VERSION 5.7 ;
BUSBITCHARS "[]" ;
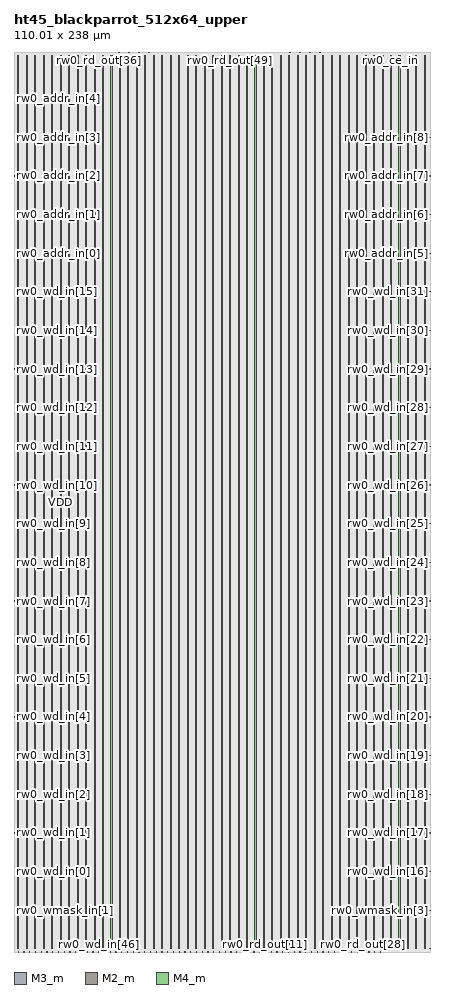
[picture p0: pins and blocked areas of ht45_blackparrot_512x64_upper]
MACRO ht45_blackparrot_512x64_upper
  FOREIGN ht45_blackparrot_512x64_upper 0 0 ;
  SYMMETRY X Y R90 ;
  SIZE 110.010 BY 238.000 ;
  CLASS COVER ;
  PIN rw0_wmask_in[0]
    DIRECTION INPUT ;
    USE SIGNAL ;
    SHAPE ABUTMENT ;
    PORT
      LAYER M3_m ;
      RECT 0.000 0.805 0.210 0.875 ;
    END
  END rw0_wmask_in[0]
  PIN rw0_wmask_in[1]
    DIRECTION INPUT ;
    USE SIGNAL ;
    SHAPE ABUTMENT ;
    PORT
      LAYER M3_m ;
      RECT 0.000 11.025 0.210 11.095 ;
    END
  END rw0_wmask_in[1]
  PIN rw0_wmask_in[2]
    DIRECTION INPUT ;
    USE SIGNAL ;
    SHAPE ABUTMENT ;
    PORT
      LAYER M3_m ;
      RECT 109.800 0.805 110.010 0.875 ;
    END
  END rw0_wmask_in[2]
  PIN rw0_wmask_in[3]
    DIRECTION INPUT ;
    USE SIGNAL ;
    SHAPE ABUTMENT ;
    PORT
      LAYER M3_m ;
      RECT 109.800 11.025 110.010 11.095 ;
    END
  END rw0_wmask_in[3]
  PIN rw0_wmask_in[4]
    DIRECTION INPUT ;
    USE SIGNAL ;
    SHAPE ABUTMENT ;
    PORT
      LAYER M2_m ;
      RECT 1.105 237.790 1.175 238.000 ;
    END
  END rw0_wmask_in[4]
  PIN rw0_wmask_in[5]
    DIRECTION INPUT ;
    USE SIGNAL ;
    SHAPE ABUTMENT ;
    PORT
      LAYER M2_m ;
      RECT 3.765 237.790 3.835 238.000 ;
    END
  END rw0_wmask_in[5]
  PIN rw0_wmask_in[6]
    DIRECTION INPUT ;
    USE SIGNAL ;
    SHAPE ABUTMENT ;
    PORT
      LAYER M2_m ;
      RECT 6.425 237.790 6.495 238.000 ;
    END
  END rw0_wmask_in[6]
  PIN rw0_wmask_in[7]
    DIRECTION INPUT ;
    USE SIGNAL ;
    SHAPE ABUTMENT ;
    PORT
      LAYER M2_m ;
      RECT 9.085 237.790 9.155 238.000 ;
    END
  END rw0_wmask_in[7]
  PIN rw0_wd_in[0]
    DIRECTION INPUT ;
    USE SIGNAL ;
    SHAPE ABUTMENT ;
    PORT
      LAYER M3_m ;
      RECT 0.000 21.245 0.210 21.315 ;
    END
  END rw0_wd_in[0]
  PIN rw0_wd_in[1]
    DIRECTION INPUT ;
    USE SIGNAL ;
    SHAPE ABUTMENT ;
    PORT
      LAYER M3_m ;
      RECT 0.000 31.465 0.210 31.535 ;
    END
  END rw0_wd_in[1]
  PIN rw0_wd_in[2]
    DIRECTION INPUT ;
    USE SIGNAL ;
    SHAPE ABUTMENT ;
    PORT
      LAYER M3_m ;
      RECT 0.000 41.685 0.210 41.755 ;
    END
  END rw0_wd_in[2]
  PIN rw0_wd_in[3]
    DIRECTION INPUT ;
    USE SIGNAL ;
    SHAPE ABUTMENT ;
    PORT
      LAYER M3_m ;
      RECT 0.000 51.905 0.210 51.975 ;
    END
  END rw0_wd_in[3]
  PIN rw0_wd_in[4]
    DIRECTION INPUT ;
    USE SIGNAL ;
    SHAPE ABUTMENT ;
    PORT
      LAYER M3_m ;
      RECT 0.000 62.125 0.210 62.195 ;
    END
  END rw0_wd_in[4]
  PIN rw0_wd_in[5]
    DIRECTION INPUT ;
    USE SIGNAL ;
    SHAPE ABUTMENT ;
    PORT
      LAYER M3_m ;
      RECT 0.000 72.345 0.210 72.415 ;
    END
  END rw0_wd_in[5]
  PIN rw0_wd_in[6]
    DIRECTION INPUT ;
    USE SIGNAL ;
    SHAPE ABUTMENT ;
    PORT
      LAYER M3_m ;
      RECT 0.000 82.565 0.210 82.635 ;
    END
  END rw0_wd_in[6]
  PIN rw0_wd_in[7]
    DIRECTION INPUT ;
    USE SIGNAL ;
    SHAPE ABUTMENT ;
    PORT
      LAYER M3_m ;
      RECT 0.000 92.785 0.210 92.855 ;
    END
  END rw0_wd_in[7]
  PIN rw0_wd_in[8]
    DIRECTION INPUT ;
    USE SIGNAL ;
    SHAPE ABUTMENT ;
    PORT
      LAYER M3_m ;
      RECT 0.000 103.005 0.210 103.075 ;
    END
  END rw0_wd_in[8]
  PIN rw0_wd_in[9]
    DIRECTION INPUT ;
    USE SIGNAL ;
    SHAPE ABUTMENT ;
    PORT
      LAYER M3_m ;
      RECT 0.000 113.225 0.210 113.295 ;
    END
  END rw0_wd_in[9]
  PIN rw0_wd_in[10]
    DIRECTION INPUT ;
    USE SIGNAL ;
    SHAPE ABUTMENT ;
    PORT
      LAYER M3_m ;
      RECT 0.000 123.445 0.210 123.515 ;
    END
  END rw0_wd_in[10]
  PIN rw0_wd_in[11]
    DIRECTION INPUT ;
    USE SIGNAL ;
    SHAPE ABUTMENT ;
    PORT
      LAYER M3_m ;
      RECT 0.000 133.665 0.210 133.735 ;
    END
  END rw0_wd_in[11]
  PIN rw0_wd_in[12]
    DIRECTION INPUT ;
    USE SIGNAL ;
    SHAPE ABUTMENT ;
    PORT
      LAYER M3_m ;
      RECT 0.000 143.885 0.210 143.955 ;
    END
  END rw0_wd_in[12]
  PIN rw0_wd_in[13]
    DIRECTION INPUT ;
    USE SIGNAL ;
    SHAPE ABUTMENT ;
    PORT
      LAYER M3_m ;
      RECT 0.000 154.105 0.210 154.175 ;
    END
  END rw0_wd_in[13]
  PIN rw0_wd_in[14]
    DIRECTION INPUT ;
    USE SIGNAL ;
    SHAPE ABUTMENT ;
    PORT
      LAYER M3_m ;
      RECT 0.000 164.325 0.210 164.395 ;
    END
  END rw0_wd_in[14]
  PIN rw0_wd_in[15]
    DIRECTION INPUT ;
    USE SIGNAL ;
    SHAPE ABUTMENT ;
    PORT
      LAYER M3_m ;
      RECT 0.000 174.545 0.210 174.615 ;
    END
  END rw0_wd_in[15]
  PIN rw0_wd_in[16]
    DIRECTION INPUT ;
    USE SIGNAL ;
    SHAPE ABUTMENT ;
    PORT
      LAYER M3_m ;
      RECT 109.800 21.245 110.010 21.315 ;
    END
  END rw0_wd_in[16]
  PIN rw0_wd_in[17]
    DIRECTION INPUT ;
    USE SIGNAL ;
    SHAPE ABUTMENT ;
    PORT
      LAYER M3_m ;
      RECT 109.800 31.465 110.010 31.535 ;
    END
  END rw0_wd_in[17]
  PIN rw0_wd_in[18]
    DIRECTION INPUT ;
    USE SIGNAL ;
    SHAPE ABUTMENT ;
    PORT
      LAYER M3_m ;
      RECT 109.800 41.685 110.010 41.755 ;
    END
  END rw0_wd_in[18]
  PIN rw0_wd_in[19]
    DIRECTION INPUT ;
    USE SIGNAL ;
    SHAPE ABUTMENT ;
    PORT
      LAYER M3_m ;
      RECT 109.800 51.905 110.010 51.975 ;
    END
  END rw0_wd_in[19]
  PIN rw0_wd_in[20]
    DIRECTION INPUT ;
    USE SIGNAL ;
    SHAPE ABUTMENT ;
    PORT
      LAYER M3_m ;
      RECT 109.800 62.125 110.010 62.195 ;
    END
  END rw0_wd_in[20]
  PIN rw0_wd_in[21]
    DIRECTION INPUT ;
    USE SIGNAL ;
    SHAPE ABUTMENT ;
    PORT
      LAYER M3_m ;
      RECT 109.800 72.345 110.010 72.415 ;
    END
  END rw0_wd_in[21]
  PIN rw0_wd_in[22]
    DIRECTION INPUT ;
    USE SIGNAL ;
    SHAPE ABUTMENT ;
    PORT
      LAYER M3_m ;
      RECT 109.800 82.565 110.010 82.635 ;
    END
  END rw0_wd_in[22]
  PIN rw0_wd_in[23]
    DIRECTION INPUT ;
    USE SIGNAL ;
    SHAPE ABUTMENT ;
    PORT
      LAYER M3_m ;
      RECT 109.800 92.785 110.010 92.855 ;
    END
  END rw0_wd_in[23]
  PIN rw0_wd_in[24]
    DIRECTION INPUT ;
    USE SIGNAL ;
    SHAPE ABUTMENT ;
    PORT
      LAYER M3_m ;
      RECT 109.800 103.005 110.010 103.075 ;
    END
  END rw0_wd_in[24]
  PIN rw0_wd_in[25]
    DIRECTION INPUT ;
    USE SIGNAL ;
    SHAPE ABUTMENT ;
    PORT
      LAYER M3_m ;
      RECT 109.800 113.225 110.010 113.295 ;
    END
  END rw0_wd_in[25]
  PIN rw0_wd_in[26]
    DIRECTION INPUT ;
    USE SIGNAL ;
    SHAPE ABUTMENT ;
    PORT
      LAYER M3_m ;
      RECT 109.800 123.445 110.010 123.515 ;
    END
  END rw0_wd_in[26]
  PIN rw0_wd_in[27]
    DIRECTION INPUT ;
    USE SIGNAL ;
    SHAPE ABUTMENT ;
    PORT
      LAYER M3_m ;
      RECT 109.800 133.665 110.010 133.735 ;
    END
  END rw0_wd_in[27]
  PIN rw0_wd_in[28]
    DIRECTION INPUT ;
    USE SIGNAL ;
    SHAPE ABUTMENT ;
    PORT
      LAYER M3_m ;
      RECT 109.800 143.885 110.010 143.955 ;
    END
  END rw0_wd_in[28]
  PIN rw0_wd_in[29]
    DIRECTION INPUT ;
    USE SIGNAL ;
    SHAPE ABUTMENT ;
    PORT
      LAYER M3_m ;
      RECT 109.800 154.105 110.010 154.175 ;
    END
  END rw0_wd_in[29]
  PIN rw0_wd_in[30]
    DIRECTION INPUT ;
    USE SIGNAL ;
    SHAPE ABUTMENT ;
    PORT
      LAYER M3_m ;
      RECT 109.800 164.325 110.010 164.395 ;
    END
  END rw0_wd_in[30]
  PIN rw0_wd_in[31]
    DIRECTION INPUT ;
    USE SIGNAL ;
    SHAPE ABUTMENT ;
    PORT
      LAYER M3_m ;
      RECT 109.800 174.545 110.010 174.615 ;
    END
  END rw0_wd_in[31]
  PIN rw0_wd_in[32]
    DIRECTION INPUT ;
    USE SIGNAL ;
    SHAPE ABUTMENT ;
    PORT
      LAYER M2_m ;
      RECT 1.105 0.000 1.175 0.210 ;
    END
  END rw0_wd_in[32]
  PIN rw0_wd_in[33]
    DIRECTION INPUT ;
    USE SIGNAL ;
    SHAPE ABUTMENT ;
    PORT
      LAYER M2_m ;
      RECT 2.625 0.000 2.695 0.210 ;
    END
  END rw0_wd_in[33]
  PIN rw0_wd_in[34]
    DIRECTION INPUT ;
    USE SIGNAL ;
    SHAPE ABUTMENT ;
    PORT
      LAYER M2_m ;
      RECT 4.145 0.000 4.215 0.210 ;
    END
  END rw0_wd_in[34]
  PIN rw0_wd_in[35]
    DIRECTION INPUT ;
    USE SIGNAL ;
    SHAPE ABUTMENT ;
    PORT
      LAYER M2_m ;
      RECT 5.665 0.000 5.735 0.210 ;
    END
  END rw0_wd_in[35]
  PIN rw0_wd_in[36]
    DIRECTION INPUT ;
    USE SIGNAL ;
    SHAPE ABUTMENT ;
    PORT
      LAYER M2_m ;
      RECT 7.185 0.000 7.255 0.210 ;
    END
  END rw0_wd_in[36]
  PIN rw0_wd_in[37]
    DIRECTION INPUT ;
    USE SIGNAL ;
    SHAPE ABUTMENT ;
    PORT
      LAYER M2_m ;
      RECT 8.705 0.000 8.775 0.210 ;
    END
  END rw0_wd_in[37]
  PIN rw0_wd_in[38]
    DIRECTION INPUT ;
    USE SIGNAL ;
    SHAPE ABUTMENT ;
    PORT
      LAYER M2_m ;
      RECT 10.225 0.000 10.295 0.210 ;
    END
  END rw0_wd_in[38]
  PIN rw0_wd_in[39]
    DIRECTION INPUT ;
    USE SIGNAL ;
    SHAPE ABUTMENT ;
    PORT
      LAYER M2_m ;
      RECT 11.745 0.000 11.815 0.210 ;
    END
  END rw0_wd_in[39]
  PIN rw0_wd_in[40]
    DIRECTION INPUT ;
    USE SIGNAL ;
    SHAPE ABUTMENT ;
    PORT
      LAYER M2_m ;
      RECT 13.265 0.000 13.335 0.210 ;
    END
  END rw0_wd_in[40]
  PIN rw0_wd_in[41]
    DIRECTION INPUT ;
    USE SIGNAL ;
    SHAPE ABUTMENT ;
    PORT
      LAYER M2_m ;
      RECT 14.785 0.000 14.855 0.210 ;
    END
  END rw0_wd_in[41]
  PIN rw0_wd_in[42]
    DIRECTION INPUT ;
    USE SIGNAL ;
    SHAPE ABUTMENT ;
    PORT
      LAYER M2_m ;
      RECT 16.305 0.000 16.375 0.210 ;
    END
  END rw0_wd_in[42]
  PIN rw0_wd_in[43]
    DIRECTION INPUT ;
    USE SIGNAL ;
    SHAPE ABUTMENT ;
    PORT
      LAYER M2_m ;
      RECT 17.825 0.000 17.895 0.210 ;
    END
  END rw0_wd_in[43]
  PIN rw0_wd_in[44]
    DIRECTION INPUT ;
    USE SIGNAL ;
    SHAPE ABUTMENT ;
    PORT
      LAYER M2_m ;
      RECT 19.345 0.000 19.415 0.210 ;
    END
  END rw0_wd_in[44]
  PIN rw0_wd_in[45]
    DIRECTION INPUT ;
    USE SIGNAL ;
    SHAPE ABUTMENT ;
    PORT
      LAYER M2_m ;
      RECT 20.865 0.000 20.935 0.210 ;
    END
  END rw0_wd_in[45]
  PIN rw0_wd_in[46]
    DIRECTION INPUT ;
    USE SIGNAL ;
    SHAPE ABUTMENT ;
    PORT
      LAYER M2_m ;
      RECT 22.385 0.000 22.455 0.210 ;
    END
  END rw0_wd_in[46]
  PIN rw0_wd_in[47]
    DIRECTION INPUT ;
    USE SIGNAL ;
    SHAPE ABUTMENT ;
    PORT
      LAYER M2_m ;
      RECT 23.905 0.000 23.975 0.210 ;
    END
  END rw0_wd_in[47]
  PIN rw0_wd_in[48]
    DIRECTION INPUT ;
    USE SIGNAL ;
    SHAPE ABUTMENT ;
    PORT
      LAYER M2_m ;
      RECT 25.425 0.000 25.495 0.210 ;
    END
  END rw0_wd_in[48]
  PIN rw0_wd_in[49]
    DIRECTION INPUT ;
    USE SIGNAL ;
    SHAPE ABUTMENT ;
    PORT
      LAYER M2_m ;
      RECT 26.945 0.000 27.015 0.210 ;
    END
  END rw0_wd_in[49]
  PIN rw0_wd_in[50]
    DIRECTION INPUT ;
    USE SIGNAL ;
    SHAPE ABUTMENT ;
    PORT
      LAYER M2_m ;
      RECT 28.465 0.000 28.535 0.210 ;
    END
  END rw0_wd_in[50]
  PIN rw0_wd_in[51]
    DIRECTION INPUT ;
    USE SIGNAL ;
    SHAPE ABUTMENT ;
    PORT
      LAYER M2_m ;
      RECT 29.985 0.000 30.055 0.210 ;
    END
  END rw0_wd_in[51]
  PIN rw0_wd_in[52]
    DIRECTION INPUT ;
    USE SIGNAL ;
    SHAPE ABUTMENT ;
    PORT
      LAYER M2_m ;
      RECT 31.505 0.000 31.575 0.210 ;
    END
  END rw0_wd_in[52]
  PIN rw0_wd_in[53]
    DIRECTION INPUT ;
    USE SIGNAL ;
    SHAPE ABUTMENT ;
    PORT
      LAYER M2_m ;
      RECT 33.025 0.000 33.095 0.210 ;
    END
  END rw0_wd_in[53]
  PIN rw0_wd_in[54]
    DIRECTION INPUT ;
    USE SIGNAL ;
    SHAPE ABUTMENT ;
    PORT
      LAYER M2_m ;
      RECT 34.545 0.000 34.615 0.210 ;
    END
  END rw0_wd_in[54]
  PIN rw0_wd_in[55]
    DIRECTION INPUT ;
    USE SIGNAL ;
    SHAPE ABUTMENT ;
    PORT
      LAYER M2_m ;
      RECT 36.065 0.000 36.135 0.210 ;
    END
  END rw0_wd_in[55]
  PIN rw0_wd_in[56]
    DIRECTION INPUT ;
    USE SIGNAL ;
    SHAPE ABUTMENT ;
    PORT
      LAYER M2_m ;
      RECT 37.585 0.000 37.655 0.210 ;
    END
  END rw0_wd_in[56]
  PIN rw0_wd_in[57]
    DIRECTION INPUT ;
    USE SIGNAL ;
    SHAPE ABUTMENT ;
    PORT
      LAYER M2_m ;
      RECT 39.105 0.000 39.175 0.210 ;
    END
  END rw0_wd_in[57]
  PIN rw0_wd_in[58]
    DIRECTION INPUT ;
    USE SIGNAL ;
    SHAPE ABUTMENT ;
    PORT
      LAYER M2_m ;
      RECT 40.625 0.000 40.695 0.210 ;
    END
  END rw0_wd_in[58]
  PIN rw0_wd_in[59]
    DIRECTION INPUT ;
    USE SIGNAL ;
    SHAPE ABUTMENT ;
    PORT
      LAYER M2_m ;
      RECT 42.145 0.000 42.215 0.210 ;
    END
  END rw0_wd_in[59]
  PIN rw0_wd_in[60]
    DIRECTION INPUT ;
    USE SIGNAL ;
    SHAPE ABUTMENT ;
    PORT
      LAYER M2_m ;
      RECT 43.665 0.000 43.735 0.210 ;
    END
  END rw0_wd_in[60]
  PIN rw0_wd_in[61]
    DIRECTION INPUT ;
    USE SIGNAL ;
    SHAPE ABUTMENT ;
    PORT
      LAYER M2_m ;
      RECT 45.185 0.000 45.255 0.210 ;
    END
  END rw0_wd_in[61]
  PIN rw0_wd_in[62]
    DIRECTION INPUT ;
    USE SIGNAL ;
    SHAPE ABUTMENT ;
    PORT
      LAYER M2_m ;
      RECT 46.705 0.000 46.775 0.210 ;
    END
  END rw0_wd_in[62]
  PIN rw0_wd_in[63]
    DIRECTION INPUT ;
    USE SIGNAL ;
    SHAPE ABUTMENT ;
    PORT
      LAYER M2_m ;
      RECT 48.225 0.000 48.295 0.210 ;
    END
  END rw0_wd_in[63]
  PIN rw0_rd_out[0]
    DIRECTION OUTPUT ;
    USE SIGNAL ;
    SHAPE ABUTMENT ;
    PORT
      LAYER M2_m ;
      RECT 49.745 0.000 49.815 0.210 ;
    END
  END rw0_rd_out[0]
  PIN rw0_rd_out[1]
    DIRECTION OUTPUT ;
    USE SIGNAL ;
    SHAPE ABUTMENT ;
    PORT
      LAYER M2_m ;
      RECT 51.265 0.000 51.335 0.210 ;
    END
  END rw0_rd_out[1]
  PIN rw0_rd_out[2]
    DIRECTION OUTPUT ;
    USE SIGNAL ;
    SHAPE ABUTMENT ;
    PORT
      LAYER M2_m ;
      RECT 52.785 0.000 52.855 0.210 ;
    END
  END rw0_rd_out[2]
  PIN rw0_rd_out[3]
    DIRECTION OUTPUT ;
    USE SIGNAL ;
    SHAPE ABUTMENT ;
    PORT
      LAYER M2_m ;
      RECT 54.305 0.000 54.375 0.210 ;
    END
  END rw0_rd_out[3]
  PIN rw0_rd_out[4]
    DIRECTION OUTPUT ;
    USE SIGNAL ;
    SHAPE ABUTMENT ;
    PORT
      LAYER M2_m ;
      RECT 55.825 0.000 55.895 0.210 ;
    END
  END rw0_rd_out[4]
  PIN rw0_rd_out[5]
    DIRECTION OUTPUT ;
    USE SIGNAL ;
    SHAPE ABUTMENT ;
    PORT
      LAYER M2_m ;
      RECT 57.345 0.000 57.415 0.210 ;
    END
  END rw0_rd_out[5]
  PIN rw0_rd_out[6]
    DIRECTION OUTPUT ;
    USE SIGNAL ;
    SHAPE ABUTMENT ;
    PORT
      LAYER M2_m ;
      RECT 58.865 0.000 58.935 0.210 ;
    END
  END rw0_rd_out[6]
  PIN rw0_rd_out[7]
    DIRECTION OUTPUT ;
    USE SIGNAL ;
    SHAPE ABUTMENT ;
    PORT
      LAYER M2_m ;
      RECT 60.385 0.000 60.455 0.210 ;
    END
  END rw0_rd_out[7]
  PIN rw0_rd_out[8]
    DIRECTION OUTPUT ;
    USE SIGNAL ;
    SHAPE ABUTMENT ;
    PORT
      LAYER M2_m ;
      RECT 61.905 0.000 61.975 0.210 ;
    END
  END rw0_rd_out[8]
  PIN rw0_rd_out[9]
    DIRECTION OUTPUT ;
    USE SIGNAL ;
    SHAPE ABUTMENT ;
    PORT
      LAYER M2_m ;
      RECT 63.425 0.000 63.495 0.210 ;
    END
  END rw0_rd_out[9]
  PIN rw0_rd_out[10]
    DIRECTION OUTPUT ;
    USE SIGNAL ;
    SHAPE ABUTMENT ;
    PORT
      LAYER M2_m ;
      RECT 64.945 0.000 65.015 0.210 ;
    END
  END rw0_rd_out[10]
  PIN rw0_rd_out[11]
    DIRECTION OUTPUT ;
    USE SIGNAL ;
    SHAPE ABUTMENT ;
    PORT
      LAYER M2_m ;
      RECT 66.465 0.000 66.535 0.210 ;
    END
  END rw0_rd_out[11]
  PIN rw0_rd_out[12]
    DIRECTION OUTPUT ;
    USE SIGNAL ;
    SHAPE ABUTMENT ;
    PORT
      LAYER M2_m ;
      RECT 67.985 0.000 68.055 0.210 ;
    END
  END rw0_rd_out[12]
  PIN rw0_rd_out[13]
    DIRECTION OUTPUT ;
    USE SIGNAL ;
    SHAPE ABUTMENT ;
    PORT
      LAYER M2_m ;
      RECT 69.505 0.000 69.575 0.210 ;
    END
  END rw0_rd_out[13]
  PIN rw0_rd_out[14]
    DIRECTION OUTPUT ;
    USE SIGNAL ;
    SHAPE ABUTMENT ;
    PORT
      LAYER M2_m ;
      RECT 71.025 0.000 71.095 0.210 ;
    END
  END rw0_rd_out[14]
  PIN rw0_rd_out[15]
    DIRECTION OUTPUT ;
    USE SIGNAL ;
    SHAPE ABUTMENT ;
    PORT
      LAYER M2_m ;
      RECT 72.545 0.000 72.615 0.210 ;
    END
  END rw0_rd_out[15]
  PIN rw0_rd_out[16]
    DIRECTION OUTPUT ;
    USE SIGNAL ;
    SHAPE ABUTMENT ;
    PORT
      LAYER M2_m ;
      RECT 74.065 0.000 74.135 0.210 ;
    END
  END rw0_rd_out[16]
  PIN rw0_rd_out[17]
    DIRECTION OUTPUT ;
    USE SIGNAL ;
    SHAPE ABUTMENT ;
    PORT
      LAYER M2_m ;
      RECT 75.585 0.000 75.655 0.210 ;
    END
  END rw0_rd_out[17]
  PIN rw0_rd_out[18]
    DIRECTION OUTPUT ;
    USE SIGNAL ;
    SHAPE ABUTMENT ;
    PORT
      LAYER M2_m ;
      RECT 77.105 0.000 77.175 0.210 ;
    END
  END rw0_rd_out[18]
  PIN rw0_rd_out[19]
    DIRECTION OUTPUT ;
    USE SIGNAL ;
    SHAPE ABUTMENT ;
    PORT
      LAYER M2_m ;
      RECT 78.625 0.000 78.695 0.210 ;
    END
  END rw0_rd_out[19]
  PIN rw0_rd_out[20]
    DIRECTION OUTPUT ;
    USE SIGNAL ;
    SHAPE ABUTMENT ;
    PORT
      LAYER M2_m ;
      RECT 80.145 0.000 80.215 0.210 ;
    END
  END rw0_rd_out[20]
  PIN rw0_rd_out[21]
    DIRECTION OUTPUT ;
    USE SIGNAL ;
    SHAPE ABUTMENT ;
    PORT
      LAYER M2_m ;
      RECT 81.665 0.000 81.735 0.210 ;
    END
  END rw0_rd_out[21]
  PIN rw0_rd_out[22]
    DIRECTION OUTPUT ;
    USE SIGNAL ;
    SHAPE ABUTMENT ;
    PORT
      LAYER M2_m ;
      RECT 83.185 0.000 83.255 0.210 ;
    END
  END rw0_rd_out[22]
  PIN rw0_rd_out[23]
    DIRECTION OUTPUT ;
    USE SIGNAL ;
    SHAPE ABUTMENT ;
    PORT
      LAYER M2_m ;
      RECT 84.705 0.000 84.775 0.210 ;
    END
  END rw0_rd_out[23]
  PIN rw0_rd_out[24]
    DIRECTION OUTPUT ;
    USE SIGNAL ;
    SHAPE ABUTMENT ;
    PORT
      LAYER M2_m ;
      RECT 86.225 0.000 86.295 0.210 ;
    END
  END rw0_rd_out[24]
  PIN rw0_rd_out[25]
    DIRECTION OUTPUT ;
    USE SIGNAL ;
    SHAPE ABUTMENT ;
    PORT
      LAYER M2_m ;
      RECT 87.745 0.000 87.815 0.210 ;
    END
  END rw0_rd_out[25]
  PIN rw0_rd_out[26]
    DIRECTION OUTPUT ;
    USE SIGNAL ;
    SHAPE ABUTMENT ;
    PORT
      LAYER M2_m ;
      RECT 89.265 0.000 89.335 0.210 ;
    END
  END rw0_rd_out[26]
  PIN rw0_rd_out[27]
    DIRECTION OUTPUT ;
    USE SIGNAL ;
    SHAPE ABUTMENT ;
    PORT
      LAYER M2_m ;
      RECT 90.785 0.000 90.855 0.210 ;
    END
  END rw0_rd_out[27]
  PIN rw0_rd_out[28]
    DIRECTION OUTPUT ;
    USE SIGNAL ;
    SHAPE ABUTMENT ;
    PORT
      LAYER M2_m ;
      RECT 92.305 0.000 92.375 0.210 ;
    END
  END rw0_rd_out[28]
  PIN rw0_rd_out[29]
    DIRECTION OUTPUT ;
    USE SIGNAL ;
    SHAPE ABUTMENT ;
    PORT
      LAYER M2_m ;
      RECT 93.825 0.000 93.895 0.210 ;
    END
  END rw0_rd_out[29]
  PIN rw0_rd_out[30]
    DIRECTION OUTPUT ;
    USE SIGNAL ;
    SHAPE ABUTMENT ;
    PORT
      LAYER M2_m ;
      RECT 95.345 0.000 95.415 0.210 ;
    END
  END rw0_rd_out[30]
  PIN rw0_rd_out[31]
    DIRECTION OUTPUT ;
    USE SIGNAL ;
    SHAPE ABUTMENT ;
    PORT
      LAYER M2_m ;
      RECT 96.865 0.000 96.935 0.210 ;
    END
  END rw0_rd_out[31]
  PIN rw0_rd_out[32]
    DIRECTION OUTPUT ;
    USE SIGNAL ;
    SHAPE ABUTMENT ;
    PORT
      LAYER M2_m ;
      RECT 11.745 237.790 11.815 238.000 ;
    END
  END rw0_rd_out[32]
  PIN rw0_rd_out[33]
    DIRECTION OUTPUT ;
    USE SIGNAL ;
    SHAPE ABUTMENT ;
    PORT
      LAYER M2_m ;
      RECT 14.405 237.790 14.475 238.000 ;
    END
  END rw0_rd_out[33]
  PIN rw0_rd_out[34]
    DIRECTION OUTPUT ;
    USE SIGNAL ;
    SHAPE ABUTMENT ;
    PORT
      LAYER M2_m ;
      RECT 17.065 237.790 17.135 238.000 ;
    END
  END rw0_rd_out[34]
  PIN rw0_rd_out[35]
    DIRECTION OUTPUT ;
    USE SIGNAL ;
    SHAPE ABUTMENT ;
    PORT
      LAYER M2_m ;
      RECT 19.725 237.790 19.795 238.000 ;
    END
  END rw0_rd_out[35]
  PIN rw0_rd_out[36]
    DIRECTION OUTPUT ;
    USE SIGNAL ;
    SHAPE ABUTMENT ;
    PORT
      LAYER M2_m ;
      RECT 22.385 237.790 22.455 238.000 ;
    END
  END rw0_rd_out[36]
  PIN rw0_rd_out[37]
    DIRECTION OUTPUT ;
    USE SIGNAL ;
    SHAPE ABUTMENT ;
    PORT
      LAYER M2_m ;
      RECT 25.045 237.790 25.115 238.000 ;
    END
  END rw0_rd_out[37]
  PIN rw0_rd_out[38]
    DIRECTION OUTPUT ;
    USE SIGNAL ;
    SHAPE ABUTMENT ;
    PORT
      LAYER M2_m ;
      RECT 27.705 237.790 27.775 238.000 ;
    END
  END rw0_rd_out[38]
  PIN rw0_rd_out[39]
    DIRECTION OUTPUT ;
    USE SIGNAL ;
    SHAPE ABUTMENT ;
    PORT
      LAYER M2_m ;
      RECT 30.365 237.790 30.435 238.000 ;
    END
  END rw0_rd_out[39]
  PIN rw0_rd_out[40]
    DIRECTION OUTPUT ;
    USE SIGNAL ;
    SHAPE ABUTMENT ;
    PORT
      LAYER M2_m ;
      RECT 33.025 237.790 33.095 238.000 ;
    END
  END rw0_rd_out[40]
  PIN rw0_rd_out[41]
    DIRECTION OUTPUT ;
    USE SIGNAL ;
    SHAPE ABUTMENT ;
    PORT
      LAYER M2_m ;
      RECT 35.685 237.790 35.755 238.000 ;
    END
  END rw0_rd_out[41]
  PIN rw0_rd_out[42]
    DIRECTION OUTPUT ;
    USE SIGNAL ;
    SHAPE ABUTMENT ;
    PORT
      LAYER M2_m ;
      RECT 38.345 237.790 38.415 238.000 ;
    END
  END rw0_rd_out[42]
  PIN rw0_rd_out[43]
    DIRECTION OUTPUT ;
    USE SIGNAL ;
    SHAPE ABUTMENT ;
    PORT
      LAYER M2_m ;
      RECT 41.005 237.790 41.075 238.000 ;
    END
  END rw0_rd_out[43]
  PIN rw0_rd_out[44]
    DIRECTION OUTPUT ;
    USE SIGNAL ;
    SHAPE ABUTMENT ;
    PORT
      LAYER M2_m ;
      RECT 43.665 237.790 43.735 238.000 ;
    END
  END rw0_rd_out[44]
  PIN rw0_rd_out[45]
    DIRECTION OUTPUT ;
    USE SIGNAL ;
    SHAPE ABUTMENT ;
    PORT
      LAYER M2_m ;
      RECT 46.325 237.790 46.395 238.000 ;
    END
  END rw0_rd_out[45]
  PIN rw0_rd_out[46]
    DIRECTION OUTPUT ;
    USE SIGNAL ;
    SHAPE ABUTMENT ;
    PORT
      LAYER M2_m ;
      RECT 48.985 237.790 49.055 238.000 ;
    END
  END rw0_rd_out[46]
  PIN rw0_rd_out[47]
    DIRECTION OUTPUT ;
    USE SIGNAL ;
    SHAPE ABUTMENT ;
    PORT
      LAYER M2_m ;
      RECT 51.645 237.790 51.715 238.000 ;
    END
  END rw0_rd_out[47]
  PIN rw0_rd_out[48]
    DIRECTION OUTPUT ;
    USE SIGNAL ;
    SHAPE ABUTMENT ;
    PORT
      LAYER M2_m ;
      RECT 54.305 237.790 54.375 238.000 ;
    END
  END rw0_rd_out[48]
  PIN rw0_rd_out[49]
    DIRECTION OUTPUT ;
    USE SIGNAL ;
    SHAPE ABUTMENT ;
    PORT
      LAYER M2_m ;
      RECT 56.965 237.790 57.035 238.000 ;
    END
  END rw0_rd_out[49]
  PIN rw0_rd_out[50]
    DIRECTION OUTPUT ;
    USE SIGNAL ;
    SHAPE ABUTMENT ;
    PORT
      LAYER M2_m ;
      RECT 59.625 237.790 59.695 238.000 ;
    END
  END rw0_rd_out[50]
  PIN rw0_rd_out[51]
    DIRECTION OUTPUT ;
    USE SIGNAL ;
    SHAPE ABUTMENT ;
    PORT
      LAYER M2_m ;
      RECT 62.285 237.790 62.355 238.000 ;
    END
  END rw0_rd_out[51]
  PIN rw0_rd_out[52]
    DIRECTION OUTPUT ;
    USE SIGNAL ;
    SHAPE ABUTMENT ;
    PORT
      LAYER M2_m ;
      RECT 64.945 237.790 65.015 238.000 ;
    END
  END rw0_rd_out[52]
  PIN rw0_rd_out[53]
    DIRECTION OUTPUT ;
    USE SIGNAL ;
    SHAPE ABUTMENT ;
    PORT
      LAYER M2_m ;
      RECT 67.605 237.790 67.675 238.000 ;
    END
  END rw0_rd_out[53]
  PIN rw0_rd_out[54]
    DIRECTION OUTPUT ;
    USE SIGNAL ;
    SHAPE ABUTMENT ;
    PORT
      LAYER M2_m ;
      RECT 70.265 237.790 70.335 238.000 ;
    END
  END rw0_rd_out[54]
  PIN rw0_rd_out[55]
    DIRECTION OUTPUT ;
    USE SIGNAL ;
    SHAPE ABUTMENT ;
    PORT
      LAYER M2_m ;
      RECT 72.925 237.790 72.995 238.000 ;
    END
  END rw0_rd_out[55]
  PIN rw0_rd_out[56]
    DIRECTION OUTPUT ;
    USE SIGNAL ;
    SHAPE ABUTMENT ;
    PORT
      LAYER M2_m ;
      RECT 75.585 237.790 75.655 238.000 ;
    END
  END rw0_rd_out[56]
  PIN rw0_rd_out[57]
    DIRECTION OUTPUT ;
    USE SIGNAL ;
    SHAPE ABUTMENT ;
    PORT
      LAYER M2_m ;
      RECT 78.245 237.790 78.315 238.000 ;
    END
  END rw0_rd_out[57]
  PIN rw0_rd_out[58]
    DIRECTION OUTPUT ;
    USE SIGNAL ;
    SHAPE ABUTMENT ;
    PORT
      LAYER M2_m ;
      RECT 80.905 237.790 80.975 238.000 ;
    END
  END rw0_rd_out[58]
  PIN rw0_rd_out[59]
    DIRECTION OUTPUT ;
    USE SIGNAL ;
    SHAPE ABUTMENT ;
    PORT
      LAYER M2_m ;
      RECT 83.565 237.790 83.635 238.000 ;
    END
  END rw0_rd_out[59]
  PIN rw0_rd_out[60]
    DIRECTION OUTPUT ;
    USE SIGNAL ;
    SHAPE ABUTMENT ;
    PORT
      LAYER M2_m ;
      RECT 86.225 237.790 86.295 238.000 ;
    END
  END rw0_rd_out[60]
  PIN rw0_rd_out[61]
    DIRECTION OUTPUT ;
    USE SIGNAL ;
    SHAPE ABUTMENT ;
    PORT
      LAYER M2_m ;
      RECT 88.885 237.790 88.955 238.000 ;
    END
  END rw0_rd_out[61]
  PIN rw0_rd_out[62]
    DIRECTION OUTPUT ;
    USE SIGNAL ;
    SHAPE ABUTMENT ;
    PORT
      LAYER M2_m ;
      RECT 91.545 237.790 91.615 238.000 ;
    END
  END rw0_rd_out[62]
  PIN rw0_rd_out[63]
    DIRECTION OUTPUT ;
    USE SIGNAL ;
    SHAPE ABUTMENT ;
    PORT
      LAYER M2_m ;
      RECT 94.205 237.790 94.275 238.000 ;
    END
  END rw0_rd_out[63]
  PIN rw0_addr_in[0]
    DIRECTION INPUT ;
    USE SIGNAL ;
    SHAPE ABUTMENT ;
    PORT
      LAYER M3_m ;
      RECT 0.000 184.765 0.210 184.835 ;
    END
  END rw0_addr_in[0]
  PIN rw0_addr_in[1]
    DIRECTION INPUT ;
    USE SIGNAL ;
    SHAPE ABUTMENT ;
    PORT
      LAYER M3_m ;
      RECT 0.000 194.985 0.210 195.055 ;
    END
  END rw0_addr_in[1]
  PIN rw0_addr_in[2]
    DIRECTION INPUT ;
    USE SIGNAL ;
    SHAPE ABUTMENT ;
    PORT
      LAYER M3_m ;
      RECT 0.000 205.205 0.210 205.275 ;
    END
  END rw0_addr_in[2]
  PIN rw0_addr_in[3]
    DIRECTION INPUT ;
    USE SIGNAL ;
    SHAPE ABUTMENT ;
    PORT
      LAYER M3_m ;
      RECT 0.000 215.425 0.210 215.495 ;
    END
  END rw0_addr_in[3]
  PIN rw0_addr_in[4]
    DIRECTION INPUT ;
    USE SIGNAL ;
    SHAPE ABUTMENT ;
    PORT
      LAYER M3_m ;
      RECT 0.000 225.645 0.210 225.715 ;
    END
  END rw0_addr_in[4]
  PIN rw0_addr_in[5]
    DIRECTION INPUT ;
    USE SIGNAL ;
    SHAPE ABUTMENT ;
    PORT
      LAYER M3_m ;
      RECT 109.800 184.765 110.010 184.835 ;
    END
  END rw0_addr_in[5]
  PIN rw0_addr_in[6]
    DIRECTION INPUT ;
    USE SIGNAL ;
    SHAPE ABUTMENT ;
    PORT
      LAYER M3_m ;
      RECT 109.800 194.985 110.010 195.055 ;
    END
  END rw0_addr_in[6]
  PIN rw0_addr_in[7]
    DIRECTION INPUT ;
    USE SIGNAL ;
    SHAPE ABUTMENT ;
    PORT
      LAYER M3_m ;
      RECT 109.800 205.205 110.010 205.275 ;
    END
  END rw0_addr_in[7]
  PIN rw0_addr_in[8]
    DIRECTION INPUT ;
    USE SIGNAL ;
    SHAPE ABUTMENT ;
    PORT
      LAYER M3_m ;
      RECT 109.800 215.425 110.010 215.495 ;
    END
  END rw0_addr_in[8]
  PIN rw0_we_in
    DIRECTION INPUT ;
    USE SIGNAL ;
    SHAPE ABUTMENT ;
    PORT
      LAYER M2_m ;
      RECT 96.865 237.790 96.935 238.000 ;
    END
  END rw0_we_in
  PIN rw0_ce_in
    DIRECTION INPUT ;
    USE SIGNAL ;
    SHAPE ABUTMENT ;
    PORT
      LAYER M2_m ;
      RECT 99.525 237.790 99.595 238.000 ;
    END
  END rw0_ce_in
  PIN rw0_clk
    DIRECTION INPUT ;
    USE SIGNAL ;
    SHAPE ABUTMENT ;
    PORT
      LAYER M2_m ;
      RECT 102.185 237.790 102.255 238.000 ;
    END
  END rw0_clk
  PIN VSS
    DIRECTION INOUT ;
    USE GROUND ;
    PORT
      LAYER M4_m ;
      RECT 1.000 0.840 1.280 237.160 ;
      RECT 3.240 0.840 3.520 237.160 ;
      RECT 5.480 0.840 5.760 237.160 ;
      RECT 7.720 0.840 8.000 237.160 ;
      RECT 9.960 0.840 10.240 237.160 ;
      RECT 12.200 0.840 12.480 237.160 ;
      RECT 14.440 0.840 14.720 237.160 ;
      RECT 16.680 0.840 16.960 237.160 ;
      RECT 18.920 0.840 19.200 237.160 ;
      RECT 21.160 0.840 21.440 237.160 ;
      RECT 23.400 0.840 23.680 237.160 ;
      RECT 25.640 0.840 25.920 237.160 ;
      RECT 27.880 0.840 28.160 237.160 ;
      RECT 30.120 0.840 30.400 237.160 ;
      RECT 32.360 0.840 32.640 237.160 ;
      RECT 34.600 0.840 34.880 237.160 ;
      RECT 36.840 0.840 37.120 237.160 ;
      RECT 39.080 0.840 39.360 237.160 ;
      RECT 41.320 0.840 41.600 237.160 ;
      RECT 43.560 0.840 43.840 237.160 ;
      RECT 45.800 0.840 46.080 237.160 ;
      RECT 48.040 0.840 48.320 237.160 ;
      RECT 50.280 0.840 50.560 237.160 ;
      RECT 52.520 0.840 52.800 237.160 ;
      RECT 54.760 0.840 55.040 237.160 ;
      RECT 57.000 0.840 57.280 237.160 ;
      RECT 59.240 0.840 59.520 237.160 ;
      RECT 61.480 0.840 61.760 237.160 ;
      RECT 63.720 0.840 64.000 237.160 ;
      RECT 65.960 0.840 66.240 237.160 ;
      RECT 68.200 0.840 68.480 237.160 ;
      RECT 70.440 0.840 70.720 237.160 ;
      RECT 72.680 0.840 72.960 237.160 ;
      RECT 74.920 0.840 75.200 237.160 ;
      RECT 77.160 0.840 77.440 237.160 ;
      RECT 79.400 0.840 79.680 237.160 ;
      RECT 81.640 0.840 81.920 237.160 ;
      RECT 83.880 0.840 84.160 237.160 ;
      RECT 86.120 0.840 86.400 237.160 ;
      RECT 88.360 0.840 88.640 237.160 ;
      RECT 90.600 0.840 90.880 237.160 ;
      RECT 92.840 0.840 93.120 237.160 ;
      RECT 95.080 0.840 95.360 237.160 ;
      RECT 97.320 0.840 97.600 237.160 ;
      RECT 99.560 0.840 99.840 237.160 ;
      RECT 101.800 0.840 102.080 237.160 ;
      RECT 104.040 0.840 104.320 237.160 ;
      RECT 106.280 0.840 106.560 237.160 ;
      RECT 108.520 0.840 108.800 237.160 ;
    END
  END VSS
  PIN VDD
    DIRECTION INOUT ;
    USE POWER ;
    PORT
      LAYER M4_m ;
      RECT 1.000 0.840 1.280 237.160 ;
      RECT 3.240 0.840 3.520 237.160 ;
      RECT 5.480 0.840 5.760 237.160 ;
      RECT 7.720 0.840 8.000 237.160 ;
      RECT 9.960 0.840 10.240 237.160 ;
      RECT 12.200 0.840 12.480 237.160 ;
      RECT 14.440 0.840 14.720 237.160 ;
      RECT 16.680 0.840 16.960 237.160 ;
      RECT 18.920 0.840 19.200 237.160 ;
      RECT 21.160 0.840 21.440 237.160 ;
      RECT 23.400 0.840 23.680 237.160 ;
      RECT 25.640 0.840 25.920 237.160 ;
      RECT 27.880 0.840 28.160 237.160 ;
      RECT 30.120 0.840 30.400 237.160 ;
      RECT 32.360 0.840 32.640 237.160 ;
      RECT 34.600 0.840 34.880 237.160 ;
      RECT 36.840 0.840 37.120 237.160 ;
      RECT 39.080 0.840 39.360 237.160 ;
      RECT 41.320 0.840 41.600 237.160 ;
      RECT 43.560 0.840 43.840 237.160 ;
      RECT 45.800 0.840 46.080 237.160 ;
      RECT 48.040 0.840 48.320 237.160 ;
      RECT 50.280 0.840 50.560 237.160 ;
      RECT 52.520 0.840 52.800 237.160 ;
      RECT 54.760 0.840 55.040 237.160 ;
      RECT 57.000 0.840 57.280 237.160 ;
      RECT 59.240 0.840 59.520 237.160 ;
      RECT 61.480 0.840 61.760 237.160 ;
      RECT 63.720 0.840 64.000 237.160 ;
      RECT 65.960 0.840 66.240 237.160 ;
      RECT 68.200 0.840 68.480 237.160 ;
      RECT 70.440 0.840 70.720 237.160 ;
      RECT 72.680 0.840 72.960 237.160 ;
      RECT 74.920 0.840 75.200 237.160 ;
      RECT 77.160 0.840 77.440 237.160 ;
      RECT 79.400 0.840 79.680 237.160 ;
      RECT 81.640 0.840 81.920 237.160 ;
      RECT 83.880 0.840 84.160 237.160 ;
      RECT 86.120 0.840 86.400 237.160 ;
      RECT 88.360 0.840 88.640 237.160 ;
      RECT 90.600 0.840 90.880 237.160 ;
      RECT 92.840 0.840 93.120 237.160 ;
      RECT 95.080 0.840 95.360 237.160 ;
      RECT 97.320 0.840 97.600 237.160 ;
      RECT 99.560 0.840 99.840 237.160 ;
      RECT 101.800 0.840 102.080 237.160 ;
      RECT 104.040 0.840 104.320 237.160 ;
      RECT 106.280 0.840 106.560 237.160 ;
      RECT 108.520 0.840 108.800 237.160 ;
    END
  END VDD
  OBS
    LAYER M1_m ;
    RECT 0 0 110.010 238.000 ;
    LAYER M2_m ;
    RECT 0 0 110.010 238.000 ;
    LAYER M3_m ;
    RECT 0 0 110.010 238.000 ;
    LAYER M4_m ;
    RECT 0 0 110.010 238.000 ;
    LAYER OVERLAP ;
    RECT 0 0 110.010 238.000 ;
  END
END ht45_blackparrot_512x64_upper

END LIBRARY
